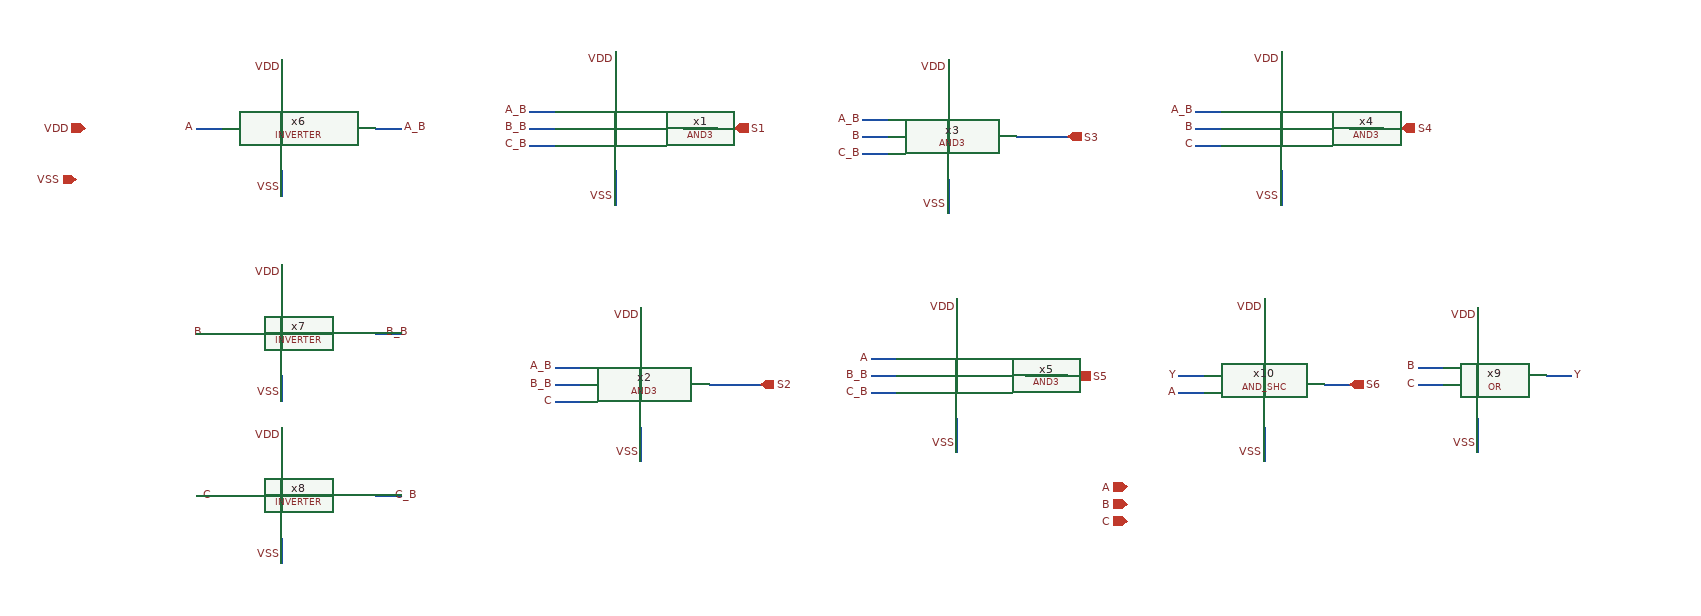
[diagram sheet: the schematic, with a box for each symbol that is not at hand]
v {xschem version=3.1.0 file_version=1.2
}
G {}
K {}
V {}
S {}
E {}
N 260 -520 290 -520 {
lab=A_B}
N 260 -500 290 -500 {
lab=B}
N 260 -480 290 -480 {
lab=C}
N 470 -500 500 -500 {
lab=S4}
N -120 -230 -90 -230 {
lab=A}
N -120 -210 -90 -210 {
lab=B_B}
N -120 -190 -90 -190 {
lab=C_B}
N 90 -210 120 -210 {
lab=S5}
N -130 -510 -100 -510 {
lab=A_B}
N -130 -490 -100 -490 {
lab=B}
N -130 -470 -100 -470 {
lab=C_B}
N 80 -490 110 -490 {
lab=S3}
N -490 -220 -460 -220 {
lab=A_B}
N -490 -200 -460 -200 {
lab=B_B}
N -490 -180 -460 -180 {
lab=C}
N -280 -200 -250 -200 {
lab=S2}
N -390 -290 -390 -260 {
lab=VDD}
N -390 -140 -390 -110 {
lab=VSS}
N 340 -300 340 -270 {
lab=VDD}
N 410 -200 440 -200 {
lab=S6}
N 240 -210 270 -210 {
lab=Y}
N 240 -190 270 -190 {
lab=Y}
N -810 -580 -810 -550 {
lab=VDD}
N -810 -450 -810 -420 {
lab=VSS}
N -700 -500 -670 -500 {
lab=A_B}
N -910 -500 -880 -500 {
lab=A}
N 590 -290 590 -260 {
lab=VDD}
N 590 -150 590 -120 {
lab=VSS}
N 670 -210 700 -210 {
lab=Y}
N 520 -220 550 -220 {
lab=B}
N 520 -200 550 -200 {
lab=C}
N 340 -270 340 -260 {
lab=VDD}
N 340 -140 340 -110 {
lab=VSS}
N -810 -340 -810 -310 {
lab=VDD}
N -810 -210 -810 -180 {
lab=VSS}
N -700 -260 -670 -260 {
lab=B_B}
N -910 -260 -880 -260 {
lab=B}
N -810 -150 -810 -120 {
lab=VDD}
N -810 -20 -810 10 {
lab=VSS}
N -700 -70 -670 -70 {
lab=C_B}
N -910 -70 -880 -70 {
lab=C}
N -30 -580 -30 -550 {
lab=VDD}
N -30 -430 -30 -400 {
lab=VSS}
N 360 -590 360 -560 {
lab=VDD}
N 360 -440 360 -410 {
lab=VSS}
N -20 -300 -20 -270 {
lab=VDD}
N -20 -150 -20 -120 {
lab=VSS}
N -310 -500 -280 -500 {
lab=S1}
N -420 -590 -420 -560 {
lab=VDD}
N -420 -440 -420 -410 {
lab=VSS}
N -520 -520 -490 -520 {
lab=A_B}
N -520 -500 -490 -500 {
lab=B_B}
N -520 -480 -490 -480 {
lab=C_B}
N -420 -560 -420 -550 {
lab=VDD}
N -420 -450 -420 -430 {
lab=VSS}
N -340 -500 -300 -500 {
lab=S1}
N -30 -440 -30 -430 {
lab=VSS}
N 50 -490 80 -490 {
lab=S3}
N -30 -550 -30 -540 {
lab=VDD}
N 360 -450 360 -440 {
lab=VSS}
N 360 -580 360 -550 {
lab=VDD}
N 440 -500 480 -500 {
lab=S4}
N -390 -150 -390 -130 {
lab=VSS}
N -390 -260 -390 -250 {
lab=VDD}
N -310 -200 -280 -200 {
lab=S2}
N -20 -160 -20 -150 {
lab=VSS}
N -20 -270 -20 -260 {
lab=VDD}
N 60 -210 110 -210 {
lab=S5}
N 590 -160 590 -150 {
lab=VSS}
N 340 -150 340 -140 {
lab=VSS}
N 340 -260 340 -250 {
lab=VDD}
C {devices/lab_pin.sym} 260 -480 0 0 {name=p11 sig_type=std_logic lab=C}
C {devices/lab_pin.sym} -120 -230 0 0 {name=p15 sig_type=std_logic lab=A}
C {devices/lab_pin.sym} -120 -190 0 0 {name=p17 sig_type=std_logic lab=C_B}
C {devices/lab_pin.sym} -130 -470 0 0 {name=p23 sig_type=std_logic lab=C_B}
C {devices/lab_pin.sym} -390 -280 0 0 {name=p25 sig_type=std_logic lab=VDD}
C {devices/lab_pin.sym} -390 -120 0 0 {name=p26 sig_type=std_logic lab=VSS}
C {devices/lab_pin.sym} -490 -220 0 0 {name=p27 sig_type=std_logic lab=A_B}
C {devices/lab_pin.sym} -490 -180 0 0 {name=p29 sig_type=std_logic lab=C}
C {devices/lab_pin.sym} 340 -290 0 0 {name=p31 sig_type=std_logic lab=VDD}
C {devices/lab_pin.sym} 240 -190 0 0 {name=p35 sig_type=std_logic lab=A}
C {devices/lab_pin.sym} -690 -260 0 1 {name=p38 sig_type=std_logic lab=B_B}
C {devices/lab_pin.sym} -810 -570 0 0 {name=p44 sig_type=std_logic lab=VDD}
C {devices/lab_pin.sym} -810 -430 0 0 {name=p45 sig_type=std_logic lab=VSS}
C {devices/lab_pin.sym} -670 -500 0 1 {name=p46 sig_type=std_logic lab=A_B}
C {devices/lab_pin.sym} -910 -500 0 0 {name=p47 sig_type=std_logic lab=A}
C {devices/lab_pin.sym} 590 -280 0 0 {name=p48 sig_type=std_logic lab=VDD}
C {devices/lab_pin.sym} 590 -130 0 0 {name=p49 sig_type=std_logic lab=VSS}
C {devices/lab_pin.sym} 700 -210 0 1 {name=p50 sig_type=std_logic lab=Y}
C {devices/opin.sym} -280 -500 0 0 {name=p33 lab=S1}
C {devices/opin.sym} -250 -200 0 0 {name=p30 lab=S2}
C {devices/opin.sym} 110 -490 0 0 {name=p24 lab=S3}
C {devices/opin.sym} 500 -500 0 0 {name=p12 lab=S4}
C {devices/opin.sym} 120 -210 0 0 {name=p18 lab=S5}
C {devices/lab_pin.sym} 340 -120 0 0 {name=p2 sig_type=std_logic lab=VSS}
C {devices/lab_pin.sym} -810 -330 0 0 {name=p32 sig_type=std_logic lab=VDD}
C {devices/lab_pin.sym} -810 -190 0 0 {name=p54 sig_type=std_logic lab=VSS}
C {devices/lab_pin.sym} -900 -260 0 0 {name=p55 sig_type=std_logic lab=B}
C {devices/lab_pin.sym} -810 -140 0 0 {name=p37 sig_type=std_logic lab=VDD}
C {devices/lab_pin.sym} -810 0 0 0 {name=p39 sig_type=std_logic lab=VSS}
C {devices/lab_pin.sym} -890 -70 0 0 {name=p36 sig_type=std_logic lab=C}
C {devices/lab_pin.sym} -680 -70 0 1 {name=p56 sig_type=std_logic lab=C_B}
C {devices/lab_pin.sym} -30 -570 0 0 {name=p40 sig_type=std_logic lab=VDD}
C {devices/lab_pin.sym} -30 -410 0 0 {name=p41 sig_type=std_logic lab=VSS}
C {devices/lab_pin.sym} 360 -580 0 0 {name=p57 sig_type=std_logic lab=VDD}
C {devices/lab_pin.sym} 360 -420 0 0 {name=p58 sig_type=std_logic lab=VSS}
C {devices/lab_pin.sym} -20 -290 0 0 {name=p42 sig_type=std_logic lab=VDD}
C {devices/lab_pin.sym} -20 -130 0 0 {name=p43 sig_type=std_logic lab=VSS}
C {devices/iopin.sym} -1040 -500 0 0 {name=p1 lab=VDD}
C {devices/iopin.sym} -1050 -440 0 0 {name=p7 lab=VSS}
C {devices/opin.sym} 440 -200 0 0 {name=p8 lab=S6}
C {devices/ipin.sym} 180 -80 0 0 {name=p13 lab=A}
C {devices/ipin.sym} 180 -60 0 0 {name=p14 lab=B}
C {devices/ipin.sym} 180 -40 0 0 {name=p53 lab=C}
C {devices/lab_pin.sym} -420 -580 0 0 {name=p59 sig_type=std_logic lab=VDD}
C {devices/lab_pin.sym} -420 -420 0 0 {name=p60 sig_type=std_logic lab=VSS}
C {AND3.sym} -340 -500 0 0 {name=x1}
C {devices/lab_pin.sym} -520 -480 0 0 {name=p61 sig_type=std_logic lab=C_B}
C {devices/lab_pin.sym} -520 -500 0 0 {name=p62 sig_type=std_logic lab=B_B}
C {devices/lab_pin.sym} -520 -520 0 0 {name=p63 sig_type=std_logic lab=A_B}
C {AND3.sym} -310 -200 0 0 {name=x2}
C {devices/lab_pin.sym} -490 -200 0 0 {name=p28 sig_type=std_logic lab=B_B}
C {devices/lab_pin.sym} -130 -490 0 0 {name=p21 sig_type=std_logic lab=B}
C {devices/lab_pin.sym} -130 -510 0 0 {name=p22 sig_type=std_logic lab=A_B}
C {AND3.sym} 50 -490 0 0 {name=x3}
C {devices/lab_pin.sym} 260 -520 0 0 {name=p9 sig_type=std_logic lab=A_B}
C {devices/lab_pin.sym} 260 -500 0 0 {name=p10 sig_type=std_logic lab=B}
C {AND3.sym} 440 -500 0 0 {name=x4}
C {devices/lab_pin.sym} -120 -210 0 0 {name=p16 sig_type=std_logic lab=B_B}
C {AND3.sym} 60 -210 0 0 {name=x5}
C {OR.sym} 610 -120 0 0 {name=x9}
C {devices/lab_pin.sym} 520 -200 0 0 {name=p51 sig_type=std_logic lab=C}
C {devices/lab_pin.sym} 520 -220 0 0 {name=p52 sig_type=std_logic lab=B}
C {devices/lab_pin.sym} 240 -210 0 0 {name=p34 sig_type=std_logic lab=Y}
C {INVERTER.sym} -810 -500 0 0 {name=x6}
C {INVERTER.sym} -810 -260 0 0 {name=x7}
C {INVERTER.sym} -810 -70 0 0 {name=x8}
C {AND_SHC.sym} 330 -270 0 0 {name=x10}
